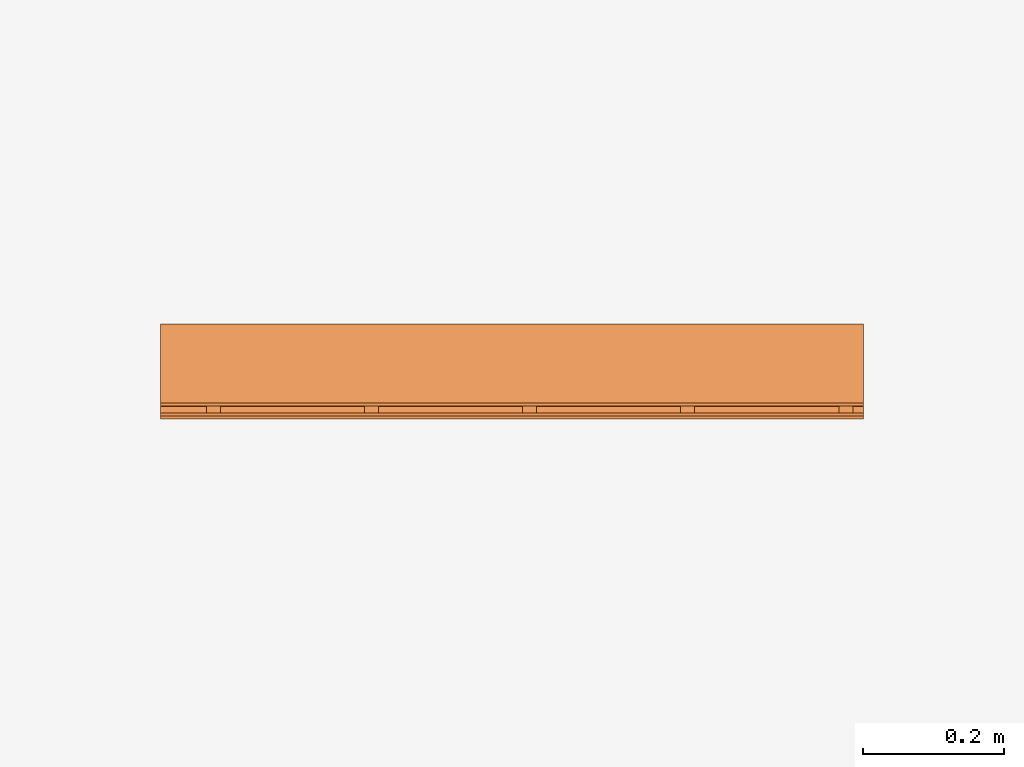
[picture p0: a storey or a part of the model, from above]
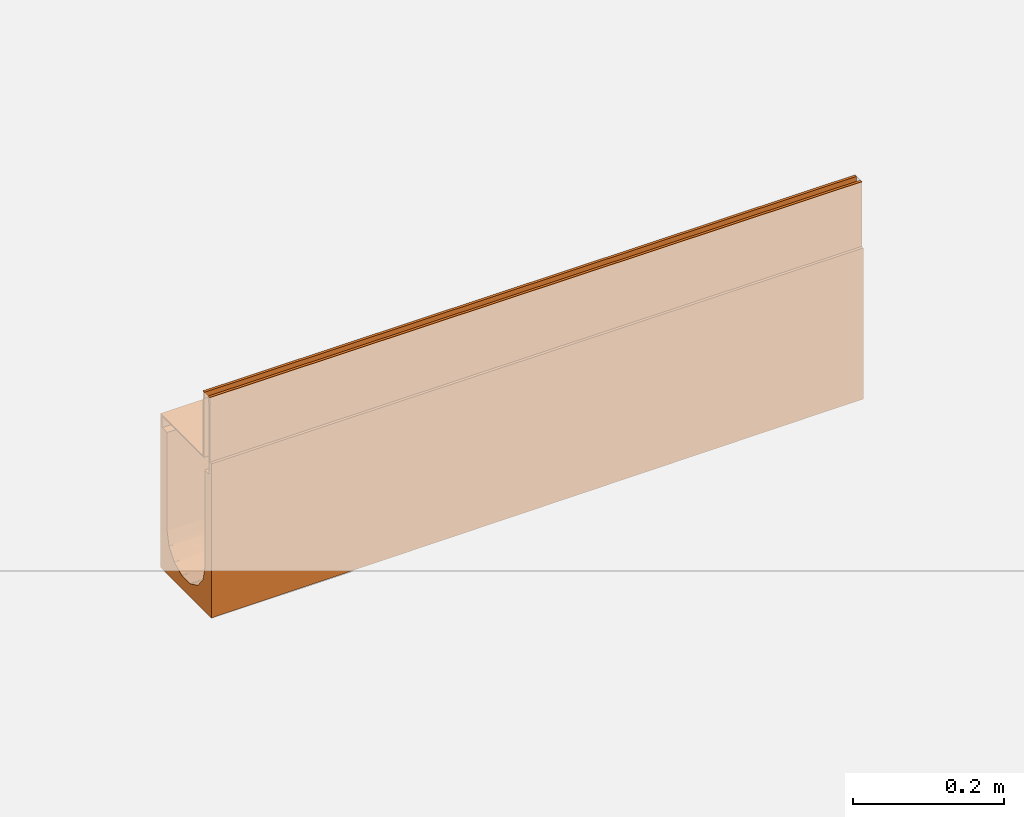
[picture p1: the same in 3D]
Properties of the parts of a building model (IFC2X3)

# File
Description: ViewDefinition [CoordinationView]
File name: 23020 - No 20 Sloping Channel - 1000mm LG - Invert Depth 225-230mm.ifc
Time: 2013-10-31T17:30:15
Written by: Autodesk Revit 2013
Made in: 20120221_2030(x64)

# IfcProject, Project Number
LongName: Project Name; Phase: Project Status

# IfcSite, Default
RefLatitude: 42, 21, 30, 344238; RefLongitude: -71, -3, -35, -194702; RefElevation: 0 mm

# IfcBuilding
Pset_BuildingCommon - NumberOfStoreys: 1
Other - Project Issue Date: Issue Date; Project Address: ## Street City, State Zip; Project Status: Project Status; Project Name: Project Name; Client Name: Owner; Project Number: Project Number

# IfcBuildingStorey, Level 1
LongName: Level 1; Elevation: 0 mm
Constraints - Elevation Base: 0; Elevation: 0 mm
Graphics - Symbol at End 2 Default: yes; Line Weight: 1; Line Pattern: Center; Color: 0; Symbol at End 1 Default: no; Symbol: M_Level Head - Circle: M_Level Head - Circle
Dimensions - Computation Height: 0 mm
Identity Data - Building Story: yes; Structural: no; Name: Level 1

# IfcBuildingElementProxy: 23020 - No 20 Sloping Channel - 1000mm LG - Invert Depth 225/230mm, Civil-Drainage-Channel-ACO-MultiDrain-M100D-Brickslot-Channel-System:23020 - No 20 Sloping Channel - 1000mm LG - Invert Depth 225/230mm:23020 - No 20 Sloping Channel - 1000mm LG - Invert Depth 225/230mm:196059
In: Level 1
Material: Steel, Galvanized, Vienite® Synthetic Resin Concrete
Dimensions - EndCap Position: 1000 mm; Brickslot Void Depth: 0 mm; Brickslot Access Unit Void Bottom Depth: -6605 mm; Brickslot Void Length: 1000 mm; Custom_Void_length: 0 mm; FloorCut_Length: -1000 mm; Brickslot Access Unit Void Depth: -6500 mm; Length: 1000 mm; Volume: 12001138 mm3; GratingLength: -1000 mm; Length Drain: -1000 mm; Floor Cut Gap: 105 mm; SlopingOverallDepth: 245 mm; Brickslot Access Unit Floor Cut Length: 500 mm; SlopingInvertDepth: 175 mm; FloorCut_Width: 135 mm; FloorCut_Depth: 250 mm; Access_Custom_Void_Length: 0 mm; Depth: 150 mm; SlopingEndOverallDepth: 250 mm; InvDepth: 80 mm; ShallowInvDepth: 55 mm; EndCap_Height: 250 mm; ShallowOverallDepth: 75 mm; SlopingEndInvertDepth: 180 mm
Construction - 23404_Universal Endcap (Male End): no; 23466_Load Class D400_Brickslot Grating_Galvanized Steel_500mm Long: no; 23460_Load Class C250_Brickslot Grating_Galvanized Steel_1000mm Long: no; 23465_Load Class D400_Brickslot Grating_Galvanized Steel_1000mm Long: yes; 23467_Load Class D400_Brickslot Access Unit_Galvanised Steel_500mm Long: no; 23404_Universal Endcap (Female End): no; 23461_Load Class C250_Brickslot Grating_Galvanized Steel_500mm Long: no; 23462_Load Class C250_Brickslot Access Unit_Galvanised Steel_500mm Long: no; Sloping Channel: yes; Constant Depth Junction Channel: no; Shallow Depth Channel with seal: no; Shallow Depth Channel: no; Constant Depth Channel: no; 23410_Sump Unit: no
Constraints - Moves With Nearby Elements: no; Level: Level: Level 1
Phasing - Phase Created: New Construction
Pset_BuildingElementProxyCommon - Reference: 23020 - No 20 Sloping Channel - 1000mm LG - Invert Depth 225/230mm
Identity Data - Manufacturer: ACO Technologies plc - ACO Water Management Division; OmniClass Title: Rainwater Removal; Fax: +44 (0)1462 815895; Maintenance guidelines: http://www.aco.co.uk/download.php?id=173; Assembly Description: Rain Water Drainage; Cost: 0; URL: www.aco.co.uk; Model Description: Channel drainage system; Watermark 1: This file is the property of ACO Technologies PLC; Product Page URL: http://www.aco.co.uk/product_detail.php?id=58; Watermarked With: BIM Manager Premium Suite; Address: ACO Business Park, Hitchin Road, Shefford, Bedfordshire, United Kingdom SG17 5TE; e-mail Sales: customersupport@aco.co.uk; Product brochure: http://www.aco.co.uk/download.php?id=173; Assembly Code: D2040; Installation guidelines: http://www.aco.co.uk/download.php?id=173; Watermark 2: This file is water marked and users are prohibited to reproduce, adapt, distribute this information; Price: POA - contact ACO; Type Comments: ACO MultiDrain M100D No 20 Sloping Channel 1000mm Long; Model: ACO MultiDrain MD Brickslot- M100D; e-mail Technical: technical@aco.co.uk; Product Code: 23020; Telephone: +44 (0)1462 816666; OmniClass Number: 23.70.50.24
Other - Revision: 1; Created By: www.aco.co.uk; Watermarked By: www.aco.co.uk
General - SerialNumber: 0; TagNumber: 0
Materials and Finishes - Channel Colour: Brown; Channel Material: Vienite® Synthetic Resin Concrete; Edge Rail Colour: Silver; Edge Rail Finish: Pre-galvanised; Edge Rail Material: Steel
Model Properties - Brickslot Access Unit Product code 23462: Load Class C250 - Brickslot Access Unit Galvanised Steel - 500mm long x 105mm high - 10mm Slot - Intake area - 10000mm²/m - 6.4 Kg; Brickslot Access Unit Product code 23467: Load Class D400 - Brickslot Access Unit Galvanised Steel - 500mm long x 105mm high - 10mm Slot - Intake area - 10000mm²/m - 6.4 Kg; Brickslot Grating Product code 23460: Load Class C250 - Brickslot Galvanised Steel - 1000mm long x 105mm high - 10mm Slot - Intake area - 10000mm²/m - 6.6 Kg; Brickslot Grating Product code 23465: Load Class D400 - Brickslot Galvanised Steel - 1000mm long x 105mm high - 10mm Slot - Intake area - 10000mm²/m - 6.6 Kg; End Cap Product code 23404: No 306 Universal End Cap - 135mm wide x 300mm long - Spigot Ø110mm x 50mm long - Silver - Polypropylene - 0.16kg; Brickslot Grating Product code 23461: Load Class C250 - Brickslot Galvanised Steel - 500mm long x 105mm high - 10mm Slot - Intake area - 10000mm²/m -3.3 Kg; Brickslot Grating Product code 23466: Load Class D400 - Brickslot Galvanised Steel - 500mm long x 105mm high - 10mm Slot - Intake area - 10000mm²/m - 3.3 Kg
Data - Product Dimensions: 1000mm x 135mm x 245mm/250mm (LxWxH); Installation - Concrete Grade: Refer to brochure; Concrete Surround Volume - Load Class A 15 - Concrete Pavement: N/A; Load Class: A 15 - D 400; Concrete Surround Volume - Load Class D 400 - Concrete Pavement: N/A; Product Standard: BS EN 1433:2002, CE marked; Invert Depth: 225mm/230mm; Pre-formed Outlet Ø: 110mm / 160mm; ACO Hydraulic Design Software: http://www.acodesign.co.uk; Channel C.S.A: N/A; Hydraulic Performance: http://www.aco.co.uk/download.php?id=173; Concrete Surround Volume - Load Class B 125 - C 250 - Concrete Pavement: N/A; Product Weight: 19.2 Kg
Green Building Properties - Edge Rail Recyclable: Fully recyclable; Channel Recyclable: Fully recyclable; Edge Rail Recycled Material Content: Between 40% - 90%; Channel Recycled Material Content: 20% minimum

# IfcOpeningElement: Recess (2)
In: Level 1
Structural - Enable Analytical Model: no; Structural: no
Constraints - Related to Mass: no; Level: Level: Level 1; Height Offset From Level: 0 mm; Room Bounding: yes
Phasing - Phase Created: New Construction
Dimensions - Thickness: 1000 mm; Area: 25000000 mm2; Perimeter: 20000 mm; Volume: 24964360000 mm3
Construction - Default Thickness: 1000 mm; Function: 0
Analytical Properties - Thermal mass: 1359800; Roughness: 1; Absorptance: 0.1; Thermal Resistance (R): 1.19474; Heat Transfer Coefficient (U): 0.837
Graphics - Coarse Scale Fill Color: 0
Materials and Finishes - Structural Material: Earth

# IfcSlab: Floor:Generic Floor - 1000mm, Floor:Generic Floor - 1000mm:193825
In: Level 1
PredefinedType: FLOOR; Material: Earth 1000 mm
Structural - Enable Analytical Model: no; Structural: no
Constraints - Related to Mass: no; Level: Level: Level 1; Height Offset From Level: 0 mm; Room Bounding: yes
Phasing - Phase Created: New Construction
Dimensions - Thickness: 1000 mm; Area: 25000000 mm2; Perimeter: 20000 mm; Volume: 24964360000 mm3
Pset_SlabCommon - Reference: Generic Floor - 1000mm; IsExternal: no; LoadBearing: yes
Construction - Default Thickness: 1000 mm; Function: 0
Analytical Properties - Thermal mass: 1359800; Roughness: 1; Absorptance: 0.1; Thermal Resistance (R): 1.19474; Heat Transfer Coefficient (U): 0.837
Graphics - Coarse Scale Fill Color: 0
Materials and Finishes - Structural Material: Earth
